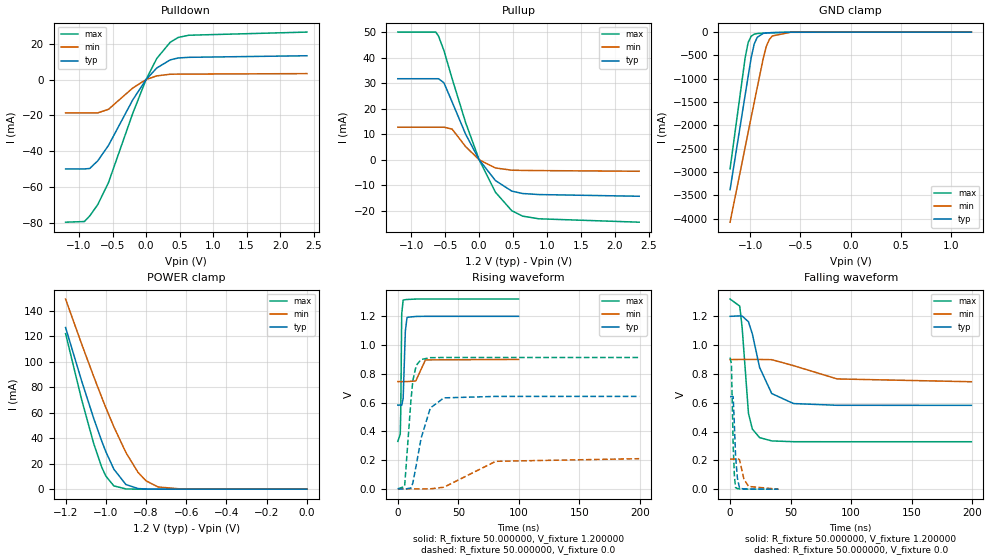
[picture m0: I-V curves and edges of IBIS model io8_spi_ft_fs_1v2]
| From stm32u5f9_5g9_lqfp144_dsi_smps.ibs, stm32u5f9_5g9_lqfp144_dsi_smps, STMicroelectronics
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|   Model io8_spi_ft_fs_1v2
[Model]  io8_spi_ft_fs_1v2
Model_type I/O
Polarity   Non-Inverting
Enable   Active-Low
Vinl =   0.360000V
Vinh =   0.840000V
Vmeas =  0.600000V
Cref =   50.000000pF
Rref =   100.000000M
Vref =   0.0V
C_comp   3.132800pF   3.069700pF   3.178000pF
[Temperature Range]   25.000000   0.140000k   -40.000000
[Pullup Reference]   1.200000V   0.900000V   1.320000V
[Pulldown Reference]   0.0V   0.0V   0.0V
[POWER Clamp Reference]   1.200000V   0.900000V   1.320000V
[GND Clamp Reference]   0.0V   0.0V   0.0V
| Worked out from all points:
|   slope of the pulldown table from 0 to 0.18 V, typ, clamps not added: 25.4 ohm
|   slope of the pullup table from 0 to 0.18 V, typ, clamps not added: 27.8 ohm
|   GND clamp passes 1 mA (typ) near -0.51 V on its own axis
|   POWER clamp passes 1 mA (typ) near -0.86 V on its own axis
|   rising waveform, R_fixture 50.000000, V_fixture 1.200000: 20-80 % time 1.28ns typ, 3.41ns min, 628ps max; typ from 0.582 V to 1.2 V
|   rising waveform, R_fixture 50.000000, V_fixture 0.0: 20-80 % time 9.77ns typ, 24.9ns min, 4.73ns max; typ from 0 V to 0.643 V
|   falling waveform, R_fixture 50.000000, V_fixture 1.200000: 20-80 % time 12.3ns typ, 30.3ns min, 5.2ns max; typ from 1.2 V to 0.582 V
|   falling waveform, R_fixture 50.000000, V_fixture 0.0: 20-80 % time 2.15ns typ, 4.11ns min, 1.55ns max; typ from 0.643 V to 0 V
[Pulldown]
|Voltage   I(typ)   I(min)   I(max)
-1.2V     -49.85mA   -18.57mA   -79.56mA
-920mV    -49.85mA   -18.57mA   -79.19mA
-840mV    -49.59mA   -18.57mA   -76.08mA
-720mV    -45.32mA   -18.57mA   -69.74mA
-560mV    -36.71mA   -16.58mA   -57.44mA
-200mV    -11.43mA   -4.74mA    -19.03mA
0V        0A         -600fA     0A
160mV     6.476mA    2.075mA    11.78mA
360mV     10.99mA    2.989mA    20.81mA
480mV     12.07mA    3.053mA    23.52mA
640mV     12.43mA    3.074mA    24.76mA
2.4V      13.31mA    3.34mA     26.51mA
[Pullup]
|Voltage   I(typ)   I(min)   I(max)
-1.2V     31.79mA    12.78mA    50.08mA
-640mV    31.79mA    12.78mA    50.08mA
-600mV    31.79mA    12.78mA    48.52mA
-520mV    30.2mA     12.78mA    42.85mA
-400mV    22.73mA    12.06mA    31.92mA
-200mV    10.05mA    5.174mA    14.59mA
0V        580fA      233pA      0A
240mV     -8.14mA    -3.2mA     -12.72mA
480mV     -12.27mA   -4.078mA   -19.94mA
640mV     -13.22mA   -4.169mA   -22.09mA
880mV     -13.63mA   -4.232mA   -23.14mA
2.36V     -14.3mA    -4.5mA     -24.47mA
[GND_clamp]
|Voltage   I(typ)   I(min)   I(max)
-1.2V     -3.379A    -4.076A    -2.932A
-1.05V    -1.35A     -2.47A     -550.7mA
-1.02V    -947.8mA   -2.149A    -221.5mA
-990mV    -552.4mA   -1.829A    -88.44mA
-960mV    -255.3mA   -1.51A     -44.87mA
-930mV    -111.8mA   -1.191A    -30.68mA
-870mV    -28.35mA   -564.6mA   -21.34mA
-840mV    -18.65mA   -309.5mA   -18.49mA
-810mV    -14.07mA   -161.6mA   -15.92mA
-780mV    -11.37mA   -83.33mA   -13.53mA
-600mV    -3.009mA   -4.321mA   -3.091mA
1.2V      0A         13.65nA    0A
[POWER_clamp]
|Voltage   I(typ)   I(min)   I(max)
-1.2V     127mA      149.4mA    122.2mA
-1.12V    84.97mA    114mA      70.27mA
-1.06V    55.51mA    88.42mA    35.67mA
-1.02V    37.63mA    72.04mA    17.17mA
-1V       29.51mA    64.13mA    10.3mA
-960mV    15.69mA    48.99mA    2.571mA
-900mV    3.624mA    28.77mA    182.8uA
-840mV    490.7uA    13.24mA    11.35uA
-800mV    116.8uA    6.532mA    1.77uA
-740mV    13.2uA     1.724mA    109.1nA
-620mV    167.4nA    79.36uA    0A
0V        0A         17.87nA    0A
[Ramp]
| variable   typ   min   max
dV/dt_r  0.38562/9.75476n   0.12550/24.88927n   0.54825/4.72385n
dV/dt_f  0.37079/12.26241n   92.42400m/30.26160n 0.59436/5.19161n
R_load = 50.000000
[Rising Waveform]
R_fixture= 50.000000
V_fixture= 1.200000
V_fixture_min= 0.900000
V_fixture_max= 1.320000
|time   V(typ)   V(min)   V(max)
0s        582mV      745.9mV    329.4mV
2.002ns   582.1mV    745.9mV    379.4mV
2.402ns   582mV      745.9mV    527.2mV
3.203ns   579.7mV    745.9mV    1.216V
4.404ns   628.5mV    745.9mV    1.313V
6.206ns   1.096V     746mV      1.316V
7.608ns   1.193V     746mV      1.317V
14.81ns   1.199V     750.1mV    1.32V
22.82ns   1.2V       896.8mV    1.32V
99.7ns    1.2V       900mV      1.32V
[Rising Waveform]
R_fixture= 50.000000
V_fixture= 0.0
V_fixture_min= 0.0
V_fixture_max= 0.0
|time   V(typ)   V(min)   V(max)
0s        1.322uV    945nV      27.63nV
5.606ns   -2.764mV   552.8nV    15.1mV
10.81ns   5.695mV    9.661uV    613.2mV
12.41ns   40.36mV    42.87uV    752.6mV
15.22ns   164.3mV    -752.2uV   858.4mV
19.22ns   351mV      -1.22mV    899.6mV
26.83ns   562mV      -443.2uV   912.1mV
38.04ns   632.5mV    10.8mV     913.3mV
80.88ns   642.7mV    191.1mV    913.4mV
199.4ns   642.8mV    209.3mV    913.4mV
[Falling Waveform]
R_fixture= 50.000000
V_fixture= 1.200000
V_fixture_min= 0.900000
V_fixture_max= 1.320000
|time   V(typ)   V(min)   V(max)
0s        1.2V       900mV      1.32V
8.008ns   1.203V     900.6mV    1.271V
10.01ns   1.202V     901.1mV    1.119V
15.22ns   1.162V     900.6mV    525.4mV
18.42ns   1.078V     900.7mV    417.2mV
24.42ns   844.9mV    900.6mV    357.9mV
34.43ns   663.9mV    899.2mV    335mV
52.45ns   594.4mV    857.6mV    329.6mV
88.49ns   582.4mV    765.4mV    329.4mV
199.4ns   582mV      745.9mV    329.4mV
[Falling Waveform]
R_fixture= 50.000000
V_fixture= 0.0
V_fixture_min= 0.0
V_fixture_max= 0.0
|time   V(typ)   V(min)   V(max)
0s        642.8mV    209.3mV    913.4mV
1.121ns   642.3mV    209.3mV    871.6mV
2.563ns   643mV      209.3mV    306mV
3.604ns   437.5mV    209.1mV    90mV
4.565ns   229.8mV    209.1mV    10.89mV
6.086ns   75.02mV    213.9mV    3.845mV
7.848ns   6.55mV     204.2mV    1.79mV
11.45ns   1.589mV    69.81mV    631.7uV
15.3ns    775.9uV    18.85mV    266.8uV
39.88ns   1.322uV    945nV      27.63nV
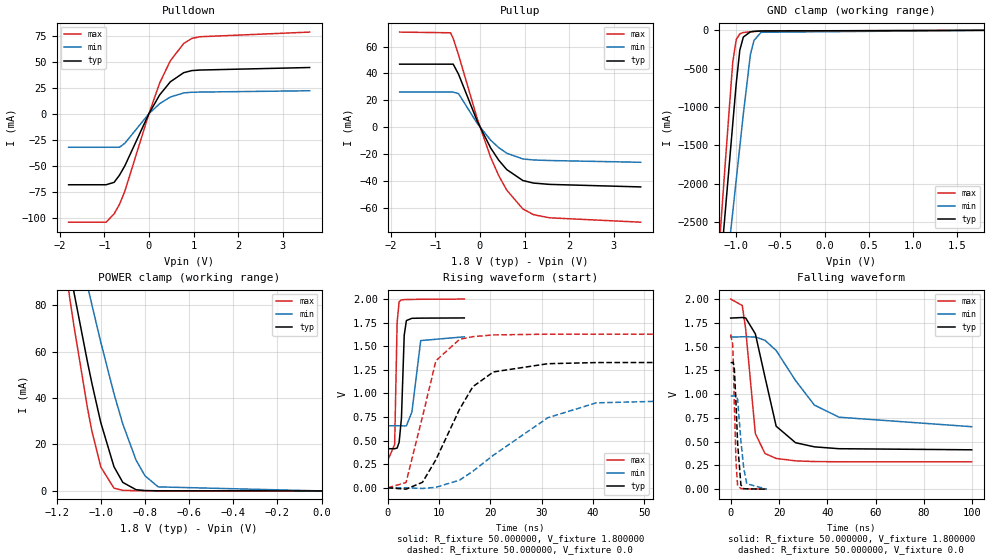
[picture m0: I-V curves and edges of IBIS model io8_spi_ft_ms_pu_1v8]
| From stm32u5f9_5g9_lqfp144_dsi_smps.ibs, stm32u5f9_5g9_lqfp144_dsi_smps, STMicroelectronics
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|   Model io8_spi_ft_ms_pu_1v8
[Model]  io8_spi_ft_ms_pu_1v8
Model_type I/O
Polarity   Non-Inverting
Enable   Active-Low
Vinl =   0.540000V
Vinh =   1.260000V
Vmeas =  0.900000V
Cref =   50.000000pF
Rref =   100.000000M
Vref =   0.0V
C_comp   3.338500pF   3.332300pF   3.378900pF
[Temperature Range]   25.000000   0.140000k   -40.000000
[Pullup Reference]   1.800000V   1.600000V   2.000000V
[Pulldown Reference]   0.0V   0.0V   0.0V
[POWER Clamp Reference]   1.800000V   1.600000V   2.000000V
[GND Clamp Reference]   0.0V   0.0V   0.0V
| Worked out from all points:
|   slope of the pulldown table from 0 to 0.27 V, typ, clamps not added: 13.6 ohm
|   slope of the pullup table from 0 to 0.27 V, typ, clamps not added: 15.9 ohm
|   GND clamp passes 1 mA (typ) near -0.51 V on its own axis
|   POWER clamp passes 1 mA (typ) near -0.86 V on its own axis
|   rising waveform, R_fixture 50.000000, V_fixture 1.800000: 20-80 % time 496ps typ, 1.04ns min, 319ps max; typ from 0.414 V to 1.8 V
|   rising waveform, R_fixture 50.000000, V_fixture 0.0: 20-80 % time 7.37ns typ, 15.8ns min, 4.01ns max; typ from 0 V to 1.33 V
|   falling waveform, R_fixture 50.000000, V_fixture 1.800000: 20-80 % time 6.93ns typ, 16.6ns min, 3.64ns max; typ from 1.8 V to 0.414 V
|   falling waveform, R_fixture 50.000000, V_fixture 0.0: 20-80 % time 1.4ns typ, 2.07ns min, 1.02ns max; typ from 1.33 V to 0 V
[Pulldown]
|Voltage   I(typ)   I(min)   I(max)
-1.8V     -68.38mA   -32.32mA   -104.4mA
-960mV    -68.38mA   -32.32mA   -104.4mA
-780mV    -66.07mA   -32.32mA   -96.42mA
-660mV    -59.2mA    -32.31mA   -87.22mA
-540mV    -50.22mA   -28.51mA   -74.66mA
0V        0A         0A         0A
240mV     18.04mA    9.599mA    29.41mA
480mV     30.68mA    16.02mA    50.95mA
780mV     39.47mA    19.98mA    67.56mA
960mV     41.44mA    20.62mA    72.37mA
1.14V     41.98mA    20.78mA    74.01mA
3.6V      44.42mA    22.05mA    78.5mA
[Pullup]
|Voltage   I(typ)   I(min)   I(max)
-1.8V     46.9mA     26.15mA    70.72mA
-660mV    46.9mA     26.15mA    70.2mA
-600mV    46.9mA     26.15mA    66.1mA
-480mV    39.44mA    24.97mA    53.77mA
-60mV     4.42mA     2.808mA    6.308mA
240mV     -15.38mA   -9.6mA     -22.37mA
420mV     -24.43mA   -15.12mA   -35.87mA
600mV     -31.41mA   -19.24mA   -46.67mA
960mV     -39.54mA   -23.52mA   -60.64mA
1.2V      -41.44mA   -24.28mA   -64.93mA
1.56V     -42.42mA   -24.69mA   -67.24mA
3.6V      -44.3mA    -26mA      -70.5mA
[GND_clamp]
|Voltage   I(typ)   I(min)   I(max)
-1.8V     -9.908A    -9.683A    -9.994A
-1.2V     -3.383A    -4.084A    -2.934A
-1.16V    -2.841A    -3.655A    -2.294A
-1.12V    -2.299A    -3.226A    -1.656A
-1.04V    -1.218A    -2.369A    -414.2mA
-1V       -684.7mA   -1.941A    -119.2mA
-960mV    -257.2mA   -1.514A    -45.66mA
-920mV    -87.03mA   -1.089A    -28.93mA
-840mV    -19.35mA   -312.8mA   -18.96mA
-800mV    -13.55mA   -132.4mA   -15.49mA
-720mV    -8.042mA   -25.66mA   -9.49mA
1.8V      0A         13.64nA    0A
[POWER_clamp]
|Voltage   I(typ)   I(min)   I(max)
-1.8V     470.9mA    433.7mA    554.6mA
-1.14V    95.28mA    122.7mA    82.88mA
-1.12V    85mA       114mA      70.34mA
-1.06V    55.55mA    88.43mA    35.73mA
-1.04V    46.38mA    80.17mA    25.83mA
-1V       29.54mA    64.14mA    10.37mA
-940mV    10.43mA    41.88mA    1.177mA
-900mV    3.66mA     28.79mA    250.5uA
-840mV    527.2uA    13.26mA    95.14uA
-800mV    153.8uA    6.55mA     88.66uA
-740mV    59.96uA    1.741mA    70.47uA
0V        0A         18.18nA    0A
[Ramp]
| variable   typ   min   max
dV/dt_r  0.79756/7.35208n   0.58789/15.72599n   0.97651/4.00336n
dV/dt_f  0.83129/6.91342n   0.56326/16.53278n   1.02742/3.63914n
R_load = 50.000000
[Rising Waveform]
R_fixture= 50.000000
V_fixture= 1.800000
V_fixture_min= 1.600000
V_fixture_max= 2.000000
|time   V(typ)   V(min)   V(max)
0s        414.5mV    657.5mV    287.7mV
1.381ns   413.5mV    657.5mV    457.7mV
1.862ns   421.4mV    657.6mV    1.752V
2.252ns   482mV      657.5mV    1.971V
2.703ns   737.3mV    657.3mV    1.991V
3.243ns   1.616V     655.8mV    1.994V
3.664ns   1.772V     656.2mV    1.995V
4.745ns   1.796V     804.3mV    1.996V
6.456ns   1.798V     1.56V      1.998V
14.95ns   1.8V       1.6V       2V
[Rising Waveform]
R_fixture= 50.000000
V_fixture= 0.0
V_fixture_min= 0.0
V_fixture_max= 0.0
|time   V(typ)   V(min)   V(max)
0s        427.1uV    509.8uV    388.3uV
3.604ns   -14.52mV   407.9uV    55.62mV
6.807ns   58.64mV    -7.109mV   753.1mV
9.409ns   297.3mV    5.39mV     1.346V
14.01ns   831.4mV    80.23mV    1.573V
16.62ns   1.072V     175.4mV    1.602V
20.62ns   1.228V     345.7mV    1.62V
31.23ns   1.315V     743mV      1.628V
40.64ns   1.327V     900.2mV    1.628V
99.7ns    1.33V      980.7mV    1.628V
[Falling Waveform]
R_fixture= 50.000000
V_fixture= 1.800000
V_fixture_min= 1.600000
V_fixture_max= 2.000000
|time   V(typ)   V(min)   V(max)
0s        1.8V       1.6V       2V
4.805ns   1.806V     1.603V     1.932V
6.206ns   1.801V     1.603V     1.684V
10.21ns   1.634V     1.601V     585mV
14.21ns   1.178V     1.566V     375.2mV
18.82ns   662.6mV    1.459V     323.7mV
26.83ns   489.1mV    1.143V     298.2mV
34.63ns   445.6mV    884.8mV    290.8mV
44.84ns   425.9mV    757.3mV    288.5mV
99.7ns    414.5mV    657.5mV    287.7mV
[Falling Waveform]
R_fixture= 50.000000
V_fixture= 0.0
V_fixture_min= 0.0
V_fixture_max= 0.0
|time   V(typ)   V(min)   V(max)
0s        1.33V      980.7mV    1.628V
810.8ps   1.333V     980.7mV    1.525V
1.051ns   1.336V     980.7mV    1.377V
1.532ns   1.265V     980.5mV    880mV
2.222ns   897.1mV    987.9mV    274.6mV
2.883ns   480.2mV    943.1mV    35.34mV
4.234ns   45.39mV    508.9mV    6.965mV
5.405ns   5.623mV    222.9mV    4.687mV
6.667ns   3.723mV    56.94mV    2.544mV
14.95ns   427.1uV    509.8uV    388.3uV
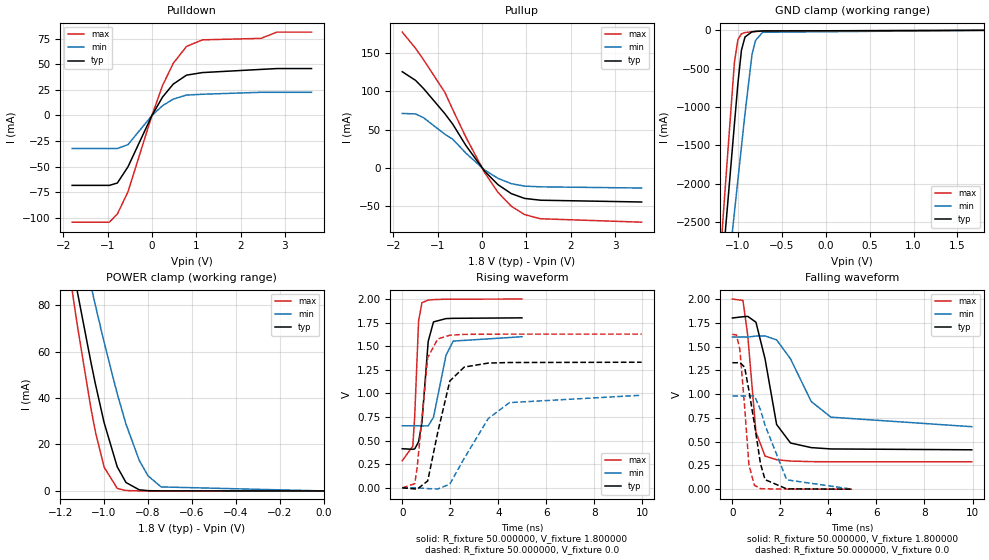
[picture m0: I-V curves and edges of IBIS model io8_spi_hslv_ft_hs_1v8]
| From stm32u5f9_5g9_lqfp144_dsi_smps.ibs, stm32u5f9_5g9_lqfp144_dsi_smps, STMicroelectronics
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|   Model io8_spi_hslv_ft_hs_1v8
[Model]  io8_spi_hslv_ft_hs_1v8
Model_type I/O
Polarity   Non-Inverting
Enable   Active-Low
Vinl =   0.540000V
Vinh =   1.260000V
Vmeas =  0.900000V
Cref =   50.000000pF
Rref =   100.000000M
Vref =   0.0V
C_comp   3.338700pF   3.332500pF   3.379000pF
[Temperature Range]   25.000000   0.140000k   -40.000000
[Pullup Reference]   1.800000V   1.600000V   2.000000V
[Pulldown Reference]   0.0V   0.0V   0.0V
[POWER Clamp Reference]   1.800000V   1.600000V   2.000000V
[GND Clamp Reference]   0.0V   0.0V   0.0V
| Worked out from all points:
|   slope of the pulldown table from 0 to 0.27 V, typ, clamps not added: 13.6 ohm
|   slope of the pullup table from 0 to 0.27 V, typ, clamps not added: 15.9 ohm
|   GND clamp passes 1 mA (typ) near -0.51 V on its own axis
|   POWER clamp passes 1 mA (typ) near -0.86 V on its own axis
|   rising waveform, R_fixture 50.000000, V_fixture 1.800000: 20-80 % time 249ps typ, 426ps min, 162ps max; typ from 0.414 V to 1.8 V
|   rising waveform, R_fixture 50.000000, V_fixture 0.0: 20-80 % time 658ps typ, 1.42ns min, 355ps max; typ from 0 V to 1.33 V
|   falling waveform, R_fixture 50.000000, V_fixture 1.800000: 20-80 % time 577ps typ, 1.21ns min, 341ps max; typ from 1.8 V to 0.414 V
|   falling waveform, R_fixture 50.000000, V_fixture 0.0: 20-80 % time 498ps typ, 773ps min, 276ps max; typ from 1.33 V to 0 V
[Pulldown]
|Voltage   I(typ)   I(min)   I(max)
-1.8V     -68.38mA   -32.32mA   -104.4mA
-960mV    -68.38mA   -32.32mA   -104.4mA
-780mV    -66.07mA   -32.32mA   -96.42mA
-540mV    -50.22mA   -28.51mA   -74.66mA
0V        0A         -300fA     0A
240mV     18.04mA    9.599mA    29.42mA
480mV     30.68mA    16.02mA    50.95mA
780mV     39.47mA    19.98mA    67.56mA
1.14V     41.99mA    20.78mA    74.01mA
2.46V     45.09mA    22.69mA    75.44mA
2.82V     45.91mA    22.69mA    81.6mA
3.6V      45.91mA    22.69mA    81.6mA
[Pullup]
|Voltage   I(typ)   I(min)   I(max)
-1.8V     125.5mA    71.12mA    177.1mA
-1.5V     114.2mA    70.55mA    156mA
-1.32V    103.6mA    65.58mA    141.1mA
-840mV    70.94mA    44.1mA     98.78mA
-660mV    57.08mA    37.47mA    76.04mA
-360mV    29.01mA    19.22mA    39.75mA
60mV      -4.209mA   -2.643mA   -6.075mA
360mV     -21.65mA   -13.44mA   -31.68mA
660mV     -33.3mA    -20.31mA   -49.69mA
960mV     -39.54mA   -23.52mA   -60.64mA
1.32V     -41.88mA   -24.45mA   -66.02mA
3.6V      -44.2mA    -26mA      -70.5mA
[GND_clamp]
|Voltage   I(typ)   I(min)   I(max)
-1.8V     -9.908A    -9.683A    -9.994A
-1.2V     -3.383A    -4.084A    -2.934A
-1.16V    -2.841A    -3.655A    -2.294A
-1.12V    -2.299A    -3.226A    -1.656A
-1.04V    -1.218A    -2.369A    -414.2mA
-1V       -684.7mA   -1.941A    -119.2mA
-960mV    -257.2mA   -1.514A    -45.66mA
-920mV    -87.03mA   -1.089A    -28.93mA
-840mV    -19.35mA   -312.8mA   -18.96mA
-800mV    -13.55mA   -132.4mA   -15.49mA
-720mV    -8.042mA   -25.66mA   -9.49mA
1.8V      0A         13.64nA    0A
[POWER_clamp]
|Voltage   I(typ)   I(min)   I(max)
-1.8V     470.8mA    433.7mA    554.6mA
-1.14V    95.25mA    122.7mA    82.82mA
-1.12V    84.97mA    114mA      70.27mA
-1.06V    55.51mA    88.42mA    35.67mA
-1.04V    46.34mA    80.15mA    25.76mA
-1V       29.51mA    64.13mA    10.3mA
-940mV    10.39mA    41.86mA    1.109mA
-900mV    3.624mA    28.77mA    182.8uA
-840mV    490.7uA    13.24mA    11.35uA
-800mV    116.8uA    6.532mA    1.77uA
-740mV    13.2uA     1.724mA    109.3nA
0V        0A         18.75nA    0A
[Ramp]
| variable   typ   min   max
dV/dt_r  0.79770/0.65691n   0.58779/1.41279n   0.97662/0.35405n
dV/dt_f  0.83158/0.57653n   0.56465/1.20099n   1.02767/0.34031n
R_load = 50.000000
[Rising Waveform]
R_fixture= 50.000000
V_fixture= 1.800000
V_fixture_min= 1.600000
V_fixture_max= 2.000000
|time   V(typ)   V(min)   V(max)
0s        414mV      656.9mV    287.3mV
440.4ps   407.8mV    657.1mV    441.4mV
520.5ps   412.4mV    657.1mV    765.8mV
680.7ps   487.7mV    657.1mV    1.767V
820.8ps   694.1mV    655.4mV    1.961V
1.081ns   1.551V     656.4mV    1.988V
1.301ns   1.757V     747.3mV    1.993V
1.822ns   1.792V     1.403V     1.998V
2.122ns   1.795V     1.554V     1.998V
4.985ns   1.8V       1.6V       1.999V
[Rising Waveform]
R_fixture= 50.000000
V_fixture= 0.0
V_fixture_min= 0.0
V_fixture_max= 0.0
|time   V(typ)   V(min)   V(max)
0s        -19.93uV   -4.87uV    106uV
520.5ps   -11.43mV   28.89uV    43.55mV
620.6ps   -14.28mV   120.4uV    212.2mV
1.061ns   73.27mV    -8.231mV   1.38V
1.481ns   590.9mV    -12.2mV    1.577V
1.982ns   1.132V     39.24mV    1.616V
2.583ns   1.279V     313.2mV    1.625V
3.584ns   1.321V     733.9mV    1.627V
4.464ns   1.327V     902.3mV    1.628V
9.97ns    1.33V      980.4mV    1.628V
[Falling Waveform]
R_fixture= 50.000000
V_fixture= 1.800000
V_fixture_min= 1.600000
V_fixture_max= 2.000000
|time   V(typ)   V(min)   V(max)
0s        1.8V       1.6V       1.999V
440.4ps   1.813V     1.6V       1.985V
640.6ps   1.817V     1.599V     1.615V
981ps     1.756V     1.61V      600.2mV
1.361ns   1.37V      1.611V     347.9mV
1.842ns   680.4mV    1.57V      309.6mV
2.422ns   485.4mV    1.37V      295.5mV
3.283ns   437mV      922mV      289.4mV
4.104ns   422.9mV    757.1mV    288mV
9.97ns    414mV      656.9mV    287.3mV
[Falling Waveform]
R_fixture= 50.000000
V_fixture= 0.0
V_fixture_min= 0.0
V_fixture_max= 0.0
|time   V(typ)   V(min)   V(max)
0s        1.33V      980.4mV    1.628V
170.2ps   1.329V     980.4mV    1.621V
310.3ps   1.333V     980.4mV    1.474V
510.5ps   1.282V     980.3mV    866.8mV
690.7ps   1.036V     981.7mV    253mV
920.9ps   683.1mV    980.3mV    40.13mV
1.171ns   267.6mV    833.5mV    5.881mV
1.361ns   100.3mV    672mV      3.822mV
2.262ns   3.004mV    98.13mV    824.3uV
4.985ns   -19.93uV   -4.87uV    106uV
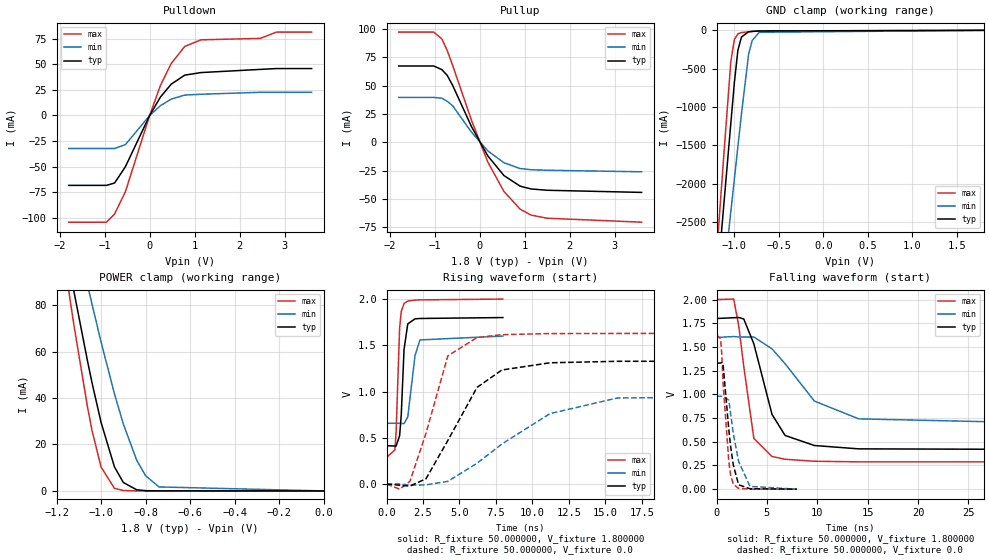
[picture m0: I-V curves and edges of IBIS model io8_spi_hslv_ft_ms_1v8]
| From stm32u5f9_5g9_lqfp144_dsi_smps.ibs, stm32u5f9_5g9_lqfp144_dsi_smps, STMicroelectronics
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|   Model io8_spi_hslv_ft_ms_1v8
[Model]  io8_spi_hslv_ft_ms_1v8
Model_type I/O
Polarity   Non-Inverting
Enable   Active-Low
Vinl =   0.540000V
Vinh =   1.260000V
Vmeas =  0.900000V
Cref =   50.000000pF
Rref =   100.000000M
Vref =   0.0V
C_comp   3.338700pF   3.332500pF   3.379000pF
[Temperature Range]   25.000000   0.140000k   -40.000000
[Pullup Reference]   1.800000V   1.600000V   2.000000V
[Pulldown Reference]   0.0V   0.0V   0.0V
[POWER Clamp Reference]   1.800000V   1.600000V   2.000000V
[GND Clamp Reference]   0.0V   0.0V   0.0V
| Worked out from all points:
|   slope of the pulldown table from 0 to 0.27 V, typ, clamps not added: 13.6 ohm
|   slope of the pullup table from 0 to 0.27 V, typ, clamps not added: 15.9 ohm
|   GND clamp passes 1 mA (typ) near -0.51 V on its own axis
|   POWER clamp passes 1 mA (typ) near -0.86 V on its own axis
|   rising waveform, R_fixture 50.000000, V_fixture 1.800000: 20-80 % time 241ps typ, 385ps min, 215ps max; typ from 0.414 V to 1.8 V
|   rising waveform, R_fixture 50.000000, V_fixture 0.0: 20-80 % time 2.75ns typ, 5.57ns min, 1.64ns max; typ from 0 V to 1.33 V
|   falling waveform, R_fixture 50.000000, V_fixture 1.800000: 20-80 % time 2.12ns typ, 4.79ns min, 1.23ns max; typ from 1.8 V to 0.414 V
|   falling waveform, R_fixture 50.000000, V_fixture 0.0: 20-80 % time 789ps typ, 1.06ns min, 619ps max; typ from 1.33 V to 0 V
[Pulldown]
|Voltage   I(typ)   I(min)   I(max)
-1.8V     -68.38mA   -32.32mA   -104.4mA
-960mV    -68.38mA   -32.32mA   -104.4mA
-780mV    -66.07mA   -32.32mA   -96.42mA
-540mV    -50.22mA   -28.51mA   -74.66mA
0V        0A         -300fA     0A
240mV     18.04mA    9.599mA    29.42mA
480mV     30.68mA    16.02mA    50.95mA
780mV     39.47mA    19.98mA    67.56mA
1.14V     41.99mA    20.78mA    74.01mA
2.46V     45.09mA    22.69mA    75.44mA
2.82V     45.91mA    22.69mA    81.6mA
3.6V      45.91mA    22.69mA    81.6mA
[Pullup]
|Voltage   I(typ)   I(min)   I(max)
-1.8V     67.41mA    39.63mA    97.36mA
-1.02V    67.41mA    39.63mA    97.36mA
-840mV    64.23mA    39.02mA    91.37mA
-720mV    59.09mA    36.19mA    80.99mA
-600mV    50.28mA    32.32mA    67.95mA
-180mV    13.77mA    8.913mA    19.32mA
180mV     -11.9mA    -7.442mA   -17.26mA
540mV     -29.31mA   -18.02mA   -43.36mA
900mV     -38.69mA   -23.13mA   -58.99mA
1.14V     -41.14mA   -24.16mA   -64.17mA
1.5V      -42.31mA   -24.64mA   -67mA
3.6V      -44.2mA    -26mA      -70.5mA
[GND_clamp]
|Voltage   I(typ)   I(min)   I(max)
-1.8V     -9.908A    -9.683A    -9.994A
-1.2V     -3.383A    -4.084A    -2.934A
-1.16V    -2.841A    -3.655A    -2.294A
-1.12V    -2.299A    -3.226A    -1.656A
-1.04V    -1.218A    -2.369A    -414.2mA
-1V       -684.7mA   -1.941A    -119.2mA
-960mV    -257.2mA   -1.514A    -45.66mA
-920mV    -87.03mA   -1.089A    -28.93mA
-840mV    -19.35mA   -312.8mA   -18.96mA
-800mV    -13.55mA   -132.4mA   -15.49mA
-720mV    -8.042mA   -25.66mA   -9.49mA
1.8V      0A         13.64nA    0A
[POWER_clamp]
|Voltage   I(typ)   I(min)   I(max)
-1.8V     470.8mA    433.7mA    554.6mA
-1.14V    95.25mA    122.7mA    82.82mA
-1.12V    84.97mA    114mA      70.27mA
-1.06V    55.51mA    88.42mA    35.67mA
-1.04V    46.34mA    80.15mA    25.76mA
-1V       29.51mA    64.13mA    10.3mA
-940mV    10.39mA    41.86mA    1.109mA
-900mV    3.624mA    28.77mA    182.8uA
-840mV    490.7uA    13.24mA    11.35uA
-800mV    116.8uA    6.532mA    1.77uA
-740mV    13.2uA     1.724mA    109.3nA
0V        0A         18.75nA    0A
[Ramp]
| variable   typ   min   max
dV/dt_r  0.79770/2.74674n   0.58816/5.56555n   0.97668/1.63689n
dV/dt_f  0.83162/2.11145n   0.56585/4.78261n   1.02769/1.22480n
R_load = 50.000000
[Rising Waveform]
R_fixture= 50.000000
V_fixture= 1.800000
V_fixture_min= 1.600000
V_fixture_max= 2.000000
|time   V(typ)   V(min)   V(max)
0s        414mV      656.9mV    287.2mV
576.6ps   410.5mV    657mV      369.1mV
656.7ps   410.2mV    657mV      561.9mV
896.9ps   521.6mV    656.6mV    1.684V
1.009ns   744.9mV    654.8mV    1.864V
1.201ns   1.455V     652.6mV    1.953V
1.457ns   1.732V     726.1mV    1.979V
1.954ns   1.786V     1.389V     1.989V
2.29ns    1.79V      1.558V     1.991V
7.976ns   1.8V       1.6V       2V
[Rising Waveform]
R_fixture= 50.000000
V_fixture= 0.0
V_fixture_min= 0.0
V_fixture_max= 0.0
|time   V(typ)   V(min)   V(max)
0s        -1.598uV   -2.119uV   -8.124uV
900.9ps   -13.12mV   220.1uV    -55.74mV
1.602ns   -22.35mV   -11.91mV   28.43mV
2.703ns   56.34mV    -9.081mV   548mV
4.204ns   470.8mV    28.7mV     1.386V
6.206ns   1.045V     224.7mV    1.584V
7.908ns   1.233V     432.6mV    1.615V
11.21ns   1.311V     761.5mV    1.627V
15.82ns   1.327V     930.1mV    1.628V
49.85ns   1.33V      980.3mV    1.628V
[Falling Waveform]
R_fixture= 50.000000
V_fixture= 1.800000
V_fixture_min= 1.600000
V_fixture_max= 2.000000
|time   V(typ)   V(min)   V(max)
0s        1.8V       1.6V       2V
1.702ns   1.808V     1.61V      2.005V
2.202ns   1.811V     1.605V     1.723V
2.703ns   1.795V     1.605V     1.294V
3.704ns   1.533V     1.605V     535.2mV
5.506ns   788.5mV    1.48V      344.3mV
6.807ns   566.4mV    1.323V     315.4mV
9.71ns    460.4mV    929.2mV    294.4mV
14.11ns   425.1mV    741.5mV    288.2mV
49.85ns   414mV      656.9mV    287.2mV
[Falling Waveform]
R_fixture= 50.000000
V_fixture= 0.0
V_fixture_min= 0.0
V_fixture_max= 0.0
|time   V(typ)   V(min)   V(max)
0s        1.33V      980.3mV    1.628V
400.4ps   1.33V      980.4mV    1.587V
512.5ps   1.336V     980.5mV    1.435V
656.7ps   1.308V     980.4mV    1.105V
1.217ns   631.3mV    938.5mV    295.4mV
1.393ns   456.9mV    801.7mV    150mV
1.666ns   254mV      584.6mV    52.97mV
2.194ns   45.95mV    293.1mV    7.826mV
3.315ns   4.547mV    29.4mV     1.467mV
7.976ns   -1.598uV   -2.119uV   -8.124uV
